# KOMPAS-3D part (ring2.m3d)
File: created 05.10.2016 12:34:28, last saved 05.10.2016 12:35:22.

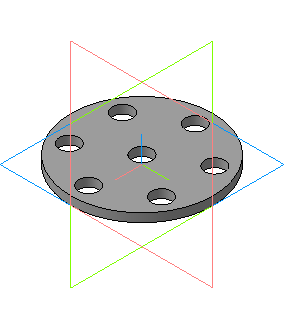
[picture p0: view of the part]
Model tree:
1. Эскиз:1
2. Операция выдавливания:1
     Расстояние 1 = 3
